One B-rep face of a CAD part: STEP entity #237.
In plain terms, the planar face has unit normal (0, -1, 0).
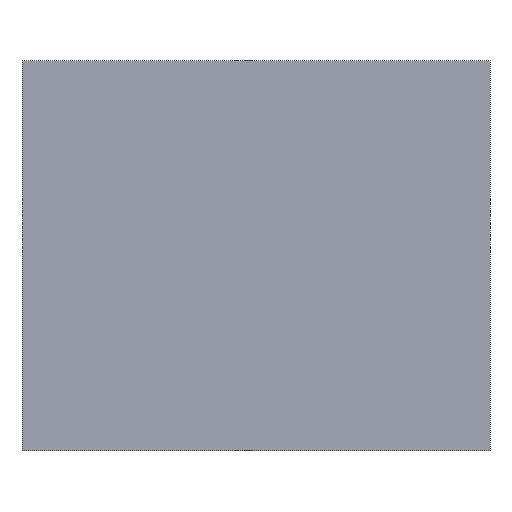
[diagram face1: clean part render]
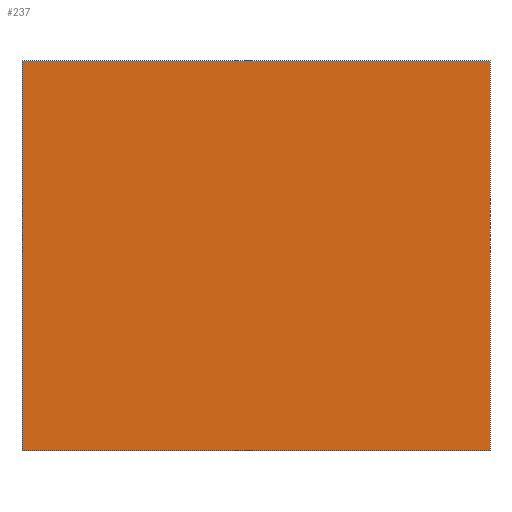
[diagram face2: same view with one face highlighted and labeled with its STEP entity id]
Its self-contained STEP definition (entity closure, numbers rounded to 3 decimals):
#21 = EDGE_CURVE('',#22,#24,#26,.T.);
#22 = VERTEX_POINT('',#23);
#23 = CARTESIAN_POINT('',(303.,-12.,-43.5));
#24 = VERTEX_POINT('',#25);
#25 = CARTESIAN_POINT('',(303.,-12.,-33.5));
#26 = SURFACE_CURVE('',#27,(#31,#43),.PCURVE_S1.);
#27 = LINE('',#28,#29);
#28 = CARTESIAN_POINT('',(303.,-12.,-43.5));
#29 = VECTOR('',#30,1.);
#30 = DIRECTION('',(0.,0.,1.));
#31 = PCURVE('',#32,#37);
#32 = PLANE('',#33);
#33 = AXIS2_PLACEMENT_3D('',#34,#35,#36);
#34 = CARTESIAN_POINT('',(303.,-12.,-43.5));
#35 = DIRECTION('',(1.,0.,0.));
#36 = DIRECTION('',(0.,0.,1.));
#37 = DEFINITIONAL_REPRESENTATION('',(#38),#42);
#38 = LINE('',#39,#40);
#39 = CARTESIAN_POINT('',(0.,0.));
#40 = VECTOR('',#41,1.);
#41 = DIRECTION('',(1.,0.));
#42 = ( GEOMETRIC_REPRESENTATION_CONTEXT(2) 
PARAMETRIC_REPRESENTATION_CONTEXT() REPRESENTATION_CONTEXT('2D SPACE',''
  ) );
#43 = PCURVE('',#44,#49);
#44 = PLANE('',#45);
#45 = AXIS2_PLACEMENT_3D('',#46,#47,#48);
#46 = CARTESIAN_POINT('',(303.,-12.,-43.5));
#47 = DIRECTION('',(0.,1.,0.));
#48 = DIRECTION('',(0.,0.,1.));
#49 = DEFINITIONAL_REPRESENTATION('',(#50),#54);
#50 = LINE('',#51,#52);
#51 = CARTESIAN_POINT('',(0.,0.));
#52 = VECTOR('',#53,1.);
#53 = DIRECTION('',(1.,0.));
#54 = ( GEOMETRIC_REPRESENTATION_CONTEXT(2) 
PARAMETRIC_REPRESENTATION_CONTEXT() REPRESENTATION_CONTEXT('2D SPACE',''
  ) );
#72 = PLANE('',#73);
#73 = AXIS2_PLACEMENT_3D('',#74,#75,#76);
#74 = CARTESIAN_POINT('',(303.,-12.,-43.5));
#75 = DIRECTION('',(0.,0.,1.));
#76 = DIRECTION('',(1.,0.,0.));
#126 = PLANE('',#127);
#127 = AXIS2_PLACEMENT_3D('',#128,#129,#130);
#128 = CARTESIAN_POINT('',(303.,-12.,-33.5));
#129 = DIRECTION('',(0.,0.,1.));
#130 = DIRECTION('',(1.,0.,0.));
#141 = EDGE_CURVE('',#142,#144,#146,.T.);
#142 = VERTEX_POINT('',#143);
#143 = CARTESIAN_POINT('',(315.,-12.,-43.5));
#144 = VERTEX_POINT('',#145);
#145 = CARTESIAN_POINT('',(315.,-12.,-33.5));
#146 = SURFACE_CURVE('',#147,(#151,#163),.PCURVE_S1.);
#147 = LINE('',#148,#149);
#148 = CARTESIAN_POINT('',(315.,-12.,-43.5));
#149 = VECTOR('',#150,1.);
#150 = DIRECTION('',(0.,0.,1.));
#151 = PCURVE('',#152,#157);
#152 = PLANE('',#153);
#153 = AXIS2_PLACEMENT_3D('',#154,#155,#156);
#154 = CARTESIAN_POINT('',(315.,-12.,-43.5));
#155 = DIRECTION('',(1.,0.,0.));
#156 = DIRECTION('',(0.,0.,1.));
#157 = DEFINITIONAL_REPRESENTATION('',(#158),#162);
#158 = LINE('',#159,#160);
#159 = CARTESIAN_POINT('',(0.,0.));
#160 = VECTOR('',#161,1.);
#161 = DIRECTION('',(1.,0.));
#162 = ( GEOMETRIC_REPRESENTATION_CONTEXT(2) 
PARAMETRIC_REPRESENTATION_CONTEXT() REPRESENTATION_CONTEXT('2D SPACE',''
  ) );
#163 = PCURVE('',#44,#164);
#164 = DEFINITIONAL_REPRESENTATION('',(#165),#169);
#165 = LINE('',#166,#167);
#166 = CARTESIAN_POINT('',(0.,12.));
#167 = VECTOR('',#168,1.);
#168 = DIRECTION('',(1.,0.));
#169 = ( GEOMETRIC_REPRESENTATION_CONTEXT(2) 
PARAMETRIC_REPRESENTATION_CONTEXT() REPRESENTATION_CONTEXT('2D SPACE',''
  ) );
#237 = ADVANCED_FACE('',(#238),#44,.F.);
#238 = FACE_BOUND('',#239,.F.);
#239 = EDGE_LOOP('',(#240,#261,#262,#283));
#240 = ORIENTED_EDGE('',*,*,#241,.F.);
#241 = EDGE_CURVE('',#22,#142,#242,.T.);
#242 = SURFACE_CURVE('',#243,(#247,#254),.PCURVE_S1.);
#243 = LINE('',#244,#245);
#244 = CARTESIAN_POINT('',(303.,-12.,-43.5));
#245 = VECTOR('',#246,1.);
#246 = DIRECTION('',(1.,0.,0.));
#247 = PCURVE('',#44,#248);
#248 = DEFINITIONAL_REPRESENTATION('',(#249),#253);
#249 = LINE('',#250,#251);
#250 = CARTESIAN_POINT('',(0.,0.));
#251 = VECTOR('',#252,1.);
#252 = DIRECTION('',(0.,1.));
#253 = ( GEOMETRIC_REPRESENTATION_CONTEXT(2) 
PARAMETRIC_REPRESENTATION_CONTEXT() REPRESENTATION_CONTEXT('2D SPACE',''
  ) );
#254 = PCURVE('',#72,#255);
#255 = DEFINITIONAL_REPRESENTATION('',(#256),#260);
#256 = LINE('',#257,#258);
#257 = CARTESIAN_POINT('',(0.,0.));
#258 = VECTOR('',#259,1.);
#259 = DIRECTION('',(1.,0.));
#260 = ( GEOMETRIC_REPRESENTATION_CONTEXT(2) 
PARAMETRIC_REPRESENTATION_CONTEXT() REPRESENTATION_CONTEXT('2D SPACE',''
  ) );
#261 = ORIENTED_EDGE('',*,*,#21,.T.);
#262 = ORIENTED_EDGE('',*,*,#263,.T.);
#263 = EDGE_CURVE('',#24,#144,#264,.T.);
#264 = SURFACE_CURVE('',#265,(#269,#276),.PCURVE_S1.);
#265 = LINE('',#266,#267);
#266 = CARTESIAN_POINT('',(303.,-12.,-33.5));
#267 = VECTOR('',#268,1.);
#268 = DIRECTION('',(1.,0.,0.));
#269 = PCURVE('',#44,#270);
#270 = DEFINITIONAL_REPRESENTATION('',(#271),#275);
#271 = LINE('',#272,#273);
#272 = CARTESIAN_POINT('',(10.,0.));
#273 = VECTOR('',#274,1.);
#274 = DIRECTION('',(0.,1.));
#275 = ( GEOMETRIC_REPRESENTATION_CONTEXT(2) 
PARAMETRIC_REPRESENTATION_CONTEXT() REPRESENTATION_CONTEXT('2D SPACE',''
  ) );
#276 = PCURVE('',#126,#277);
#277 = DEFINITIONAL_REPRESENTATION('',(#278),#282);
#278 = LINE('',#279,#280);
#279 = CARTESIAN_POINT('',(0.,0.));
#280 = VECTOR('',#281,1.);
#281 = DIRECTION('',(1.,0.));
#282 = ( GEOMETRIC_REPRESENTATION_CONTEXT(2) 
PARAMETRIC_REPRESENTATION_CONTEXT() REPRESENTATION_CONTEXT('2D SPACE',''
  ) );
#283 = ORIENTED_EDGE('',*,*,#141,.F.);
